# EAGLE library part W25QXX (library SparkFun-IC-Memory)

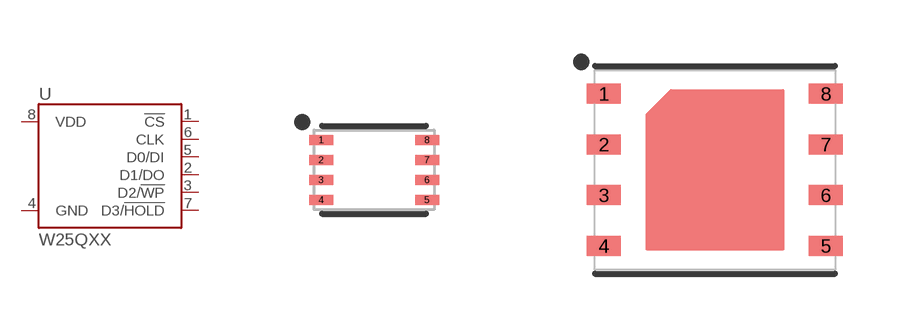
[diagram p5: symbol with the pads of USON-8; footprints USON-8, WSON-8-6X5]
Designator prefix U

## W25QXX16MBIT-3X2 (PROD_ID: IC-14905)  [USON-8]
1  !CS!
2  D1/DO
3  D2/!WP!
4  GND
5  D0/DI
6  CLK
7  D3/!HOLD!
8  VDD

## W25QXX128MBIT-6X5 (PROD_ID: IC-15107)  [WSON-8-6X5]
Pads as for USON-8

## W25QXX128MBIT-6X5-NO_CENTER (PROD_ID: IC-15107)  [WSON-8-6X5-NO_CENTERPAD]
Pads as for USON-8

## W25QXX128MBIT-6X5-SKINNY_CENTER (PROD_ID: IC-15107)  [WSON-8-6X5-SKINNY_CENTERPAD]
Pads as for USON-8

## W25QXX32MBIT-6X5 (PROD_ID: IC-15681; VALUE: W25Q32JVZPIQ)  [WSON-8-6X5]
Pads as for USON-8

## Footprint USON-8 (pad centres in mm)
USON-8. UX package with Winbond. 2x3mm. Only available up to 16Mbit.
smd 0.6 x 0.25: 1 -1.325,0.75; 2 -1.325,0.25; 3 -1.325,-0.25; 4 -1.325,-0.75; 5 1.325,-0.75; 6 1.325,-0.25; 7 1.325,0.25; 8 1.325,0.75

## Footprint WSON-8-6X5 (pad centres in mm)
smd 0.85 x 0.5: 1 -2.775,1.905; 2 -2.775,0.635; 3 -2.775,-0.635; 4 -2.775,-1.905; 5 2.775,-1.905; 6 2.775,-0.635; 7 2.775,0.635; 8 2.775,1.905

## Footprint WSON-8-6X5-NO_CENTERPAD (pad centres in mm)
smd 0.85 x 0.5: 1 -2.775,1.905; 2 -2.775,0.635; 3 -2.775,-0.635; 4 -2.775,-1.905; 5 2.775,-1.905; 6 2.775,-0.635; 7 2.775,0.635; 8 2.775,1.905

## Footprint WSON-8-6X5-SKINNY_CENTERPAD (pad centres in mm)
smd 0.85 x 0.5: 1 -2.775,1.905; 2 -2.775,0.635; 3 -2.775,-0.635; 4 -2.775,-1.905; 5 2.775,-1.905; 6 2.775,-0.635; 7 2.775,0.635; 8 2.775,1.905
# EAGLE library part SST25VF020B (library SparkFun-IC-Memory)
2Mbit Serial Flash Memory 8pin SPI Flash Datasheet

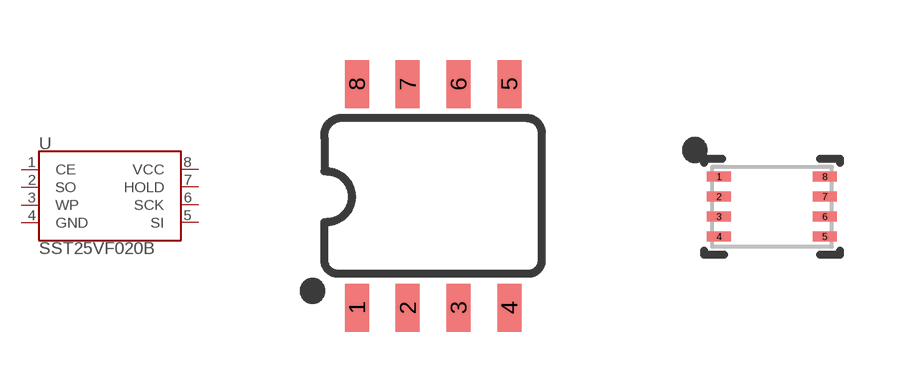
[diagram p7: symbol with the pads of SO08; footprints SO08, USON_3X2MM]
Designator prefix U

## SST25VF020BSO08_INDUSTRIAL_TEMP (DIGIKEY_PART: SST25VF020B-80-4I-SAE-TCT-ND; MANUFACTURER: Microchip; MANU_PART: SST25VF020B-80-4I-SAE-T; MOUSER_PART: 579-25VF020B8ISAET; PROD_ID: IC-15319; VALUE: 2Mbit SPI Flash)  [SO08]
1  CE
2  SO
3  WP
4  GND  pwr
5  SI
6  SCK
7  HOLD
8  VCC  pwr

## SST25VF020BUSON (DIGIKEY_PART: SST25VF020B-80-4I-Q3AE-TCT-ND; MANU_PART: SST25VF020B-80-4I-Q3AE-T; PROD_ID: IC-15716)  [USON_3X2MM]
Pads as for SO08

## SST25VF020BSO08_COMMERCIAL_TEMP (PROD_ID: IC-16021)  [SO08]
Pads as for SO08

## Footprint SO08 (pad centres in mm)
SOIC, 0.15 inch width
smd 0.6 x 1.2: 1 -1.905,-2.8; 2 -0.635,-2.8; 3 0.635,-2.8; 4 1.905,-2.8; 5 1.905,2.8; 6 0.635,2.8; 7 -0.635,2.8; 8 -1.905,2.8

## Footprint USON_3X2MM (pad centres in mm)
USON (UDFN) 3x2mm
smd 0.6 x 0.25: 1 -1.325,0.75; 2 -1.325,0.25; 3 -1.325,-0.25; 4 -1.325,-0.75; 5 1.325,-0.75; 6 1.325,-0.25; 7 1.325,0.25; 8 1.325,0.75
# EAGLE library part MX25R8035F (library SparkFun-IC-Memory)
Macronix MX25R8035F Serial Flash Low power 8Mb flash storage chip SPI interface 1-bit, 2-bit, and 4-bit storage structures Datasheet

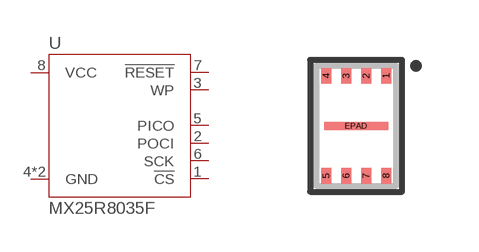
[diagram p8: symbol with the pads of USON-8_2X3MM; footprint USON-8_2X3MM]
Designator prefix U

## MX25R8035FZUIL0 (PROD_ID: IC-16921)  [USON-8_2X3MM]
1  !CS!
2  POCI
3  WP
4  GND
5  PICO
6  SCK
7  !RESET!
8  VCC
EPAD  GND

## Footprint USON-8_2X3MM (pad centres in mm)
8-USON Specifications: Pin count: 8 Package size: 2mm x 3mm Pin pitch: 0.5mm Datasheet referenced for footprint
smd 0.25 x 0.4: 1 0.75,1.25; 2 0.25,1.25; 3 -0.25,1.25; 4 -0.75,1.25; 5 -0.75,-1.25; 6 -0.25,-1.25; 7 0.25,-1.25; 8 0.75,-1.25
smd 1.6 x 0.2: EPAD 0,0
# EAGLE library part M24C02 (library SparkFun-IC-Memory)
STMicroelectronics M24C02 2k EEPROM 2k EEPROM I2C interface Write protection Datasheet

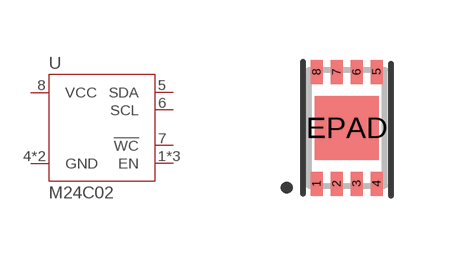
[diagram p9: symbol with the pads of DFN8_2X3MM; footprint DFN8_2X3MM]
Designator prefix U

## M24C02-FMC6TG (PROD_ID: IC-16922)  [DFN8_2X3MM]
1  EN
2  EN
3  EN
4  GND
5  SDA
6  SCL
7  !WC!
8  VCC
EPAD  GND

## Footprint DFN8_2X3MM (pad centres in mm)
UFDFPN8 Specifications: Pin count: 8 Package size: 2mm x 3mm Pin pitch: 0.5mm Datasheet referenced for footprint
smd 0.3 x 0.6: 1 -0.75,-1.4; 2 -0.25,-1.4; 3 0.25,-1.4; 4 0.75,-1.4; 5 0.75,1.4; 6 0.25,1.4; 7 -0.25,1.4; 8 -0.75,1.4
smd 1.6 x 1.6: EPAD 0,0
